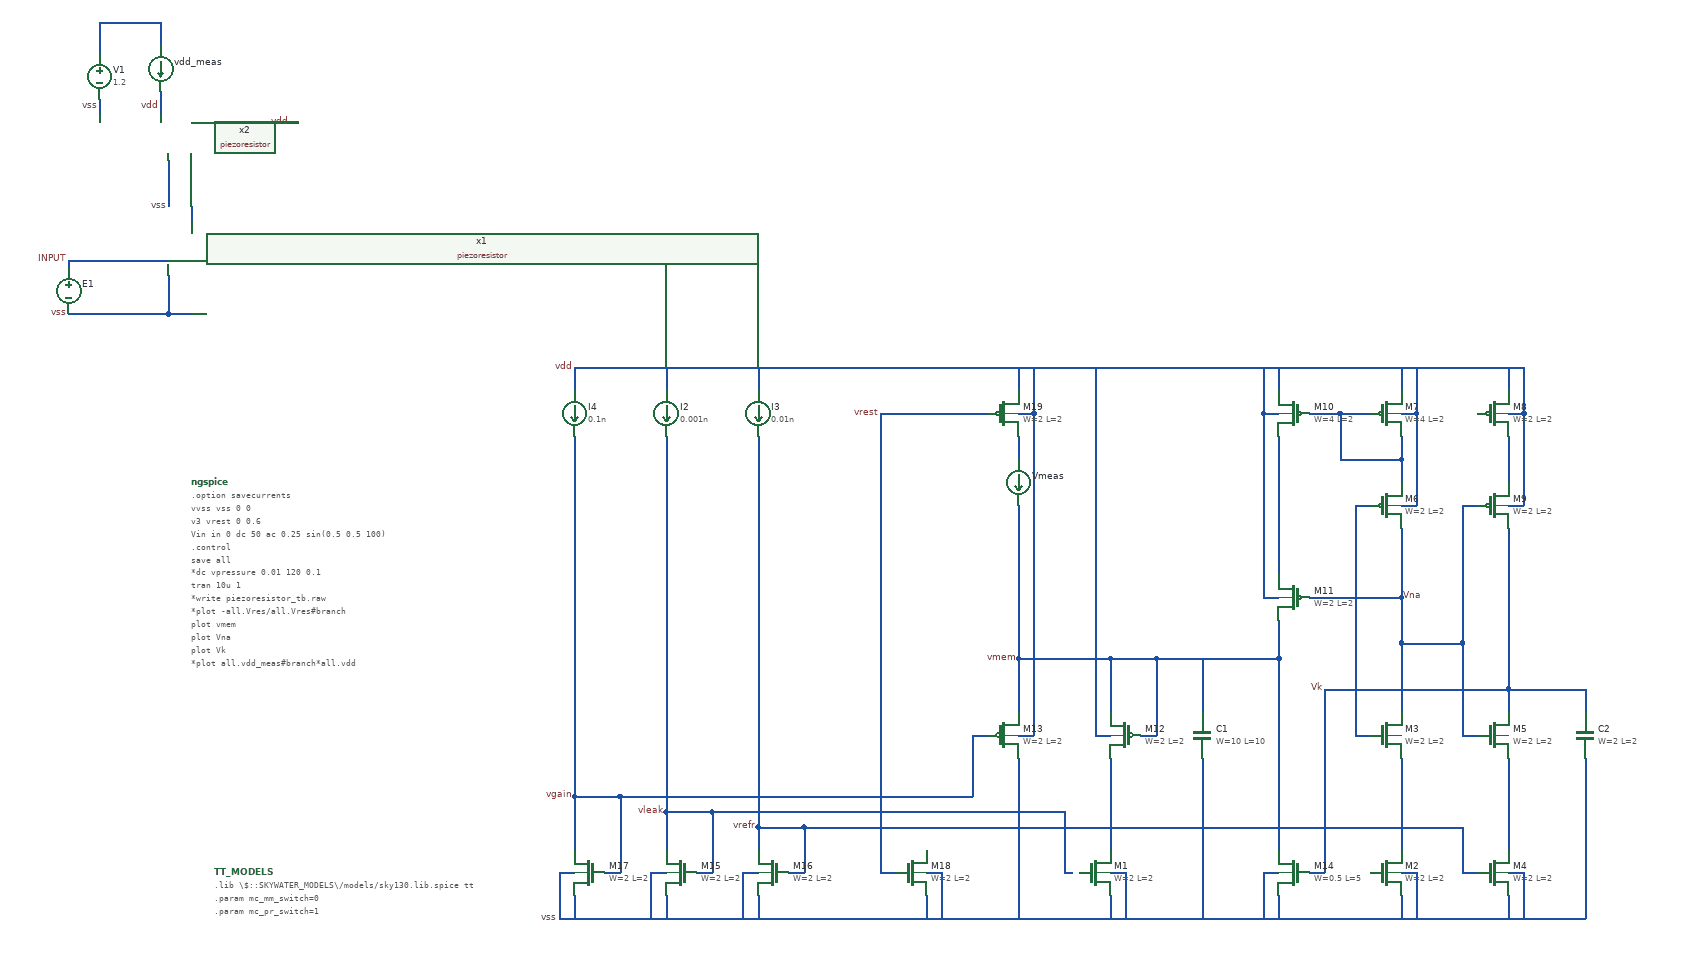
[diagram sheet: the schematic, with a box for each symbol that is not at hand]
v {xschem version=2.9.9 file_version=1.2 

* Copyright 2020 Stefan Frederik Schippers
* 
* Licensed under the Apache License, Version 2.0 (the "License");
* you may not use this file except in compliance with the License.
* You may obtain a copy of the License at
*
*     https://www.apache.org/licenses/LICENSE-2.0
*
* Unless required by applicable law or agreed to in writing, software
* distributed under the License is distributed on an "AS IS" BASIS,
* WITHOUT WARRANTIES OR CONDITIONS OF ANY KIND, either express or implied.
* See the License for the specific language governing permissions and
* limitations under the License.

}
G {}
K {}
V {}
S {}
E {}
N 1100 -1840 1230 -1840 { lab=INPUT}
N 1140 -2150 1140 -2110 { lab=#net1}
N 1140 -2150 1220 -2150 { lab=#net1}
N 1220 -2150 1220 -2120 { lab=#net1}
N 1220 -2060 1220 -2030 { lab=vdd}
N 1140 -2050 1140 -2030 { lab=vss}
N 2840 -1580 2840 -1550 { lab=#net2}
N 1880 -1700 1880 -1670 { lab=vdd}
N 2000 -1700 2000 -1670 { lab=vdd}
N 1760 -1700 1760 -1670 { lab=vdd}
N 2840 -1520 2860 -1520 { lab=vdd}
N 2840 -1640 2860 -1640 { lab=vdd}
N 2980 -1640 3000 -1640 { lab=vdd}
N 2980 -1520 3000 -1520 { lab=vdd}
N 1230 -1770 1260 -1770 { lab=vss}
N 1260 -1910 1260 -1890 { lab=#net3}
N 1100 -1770 1230 -1770 { lab=vss}
N 1230 -1970 1230 -1910 { lab=vss}
N 1100 -1840 1100 -1830 { lab=INPUT}
N 1230 -1820 1230 -1770 { lab=vss}
N 2680 -1700 2680 -1670 { lab=vdd}
N 2840 -1700 2840 -1670 { lab=vdd}
N 2980 -1700 2980 -1670 { lab=vdd}
N 2660 -1640 2680 -1640 { lab=vdd}
N 2760 -1640 2800 -1640 { lab=#net2}
N 2760 -1580 2840 -1580 { lab=#net2}
N 2760 -1640 2760 -1580 { lab=#net2}
N 2660 -1400 2680 -1400 { lab=vdd}
N 2860 -1640 2860 -1520 { lab=vdd}
N 3000 -1640 3000 -1520 { lab=vdd}
N 2840 -1610 2840 -1580 { lab=#net2}
N 2980 -1610 2980 -1550 { lab=#net4}
N 3000 -1700 3000 -1640 { lab=vdd}
N 2860 -1700 2860 -1640 { lab=vdd}
N 2660 -1700 2660 -1640 { lab=vdd}
N 2680 -1610 2680 -1430 { lab=#net5}
N 2660 -1640 2660 -1400 { lab=vdd}
N 2680 -1320 2680 -1070 { lab=vmem}
N 2840 -1340 2840 -1250 { lab=Vna}
N 2980 -1280 2980 -1250 { lab=Vk}
N 2780 -1520 2800 -1520 { lab=#net6}
N 2780 -1520 2780 -1220 { lab=#net6}
N 2780 -1220 2800 -1220 { lab=#net6}
N 2920 -1520 2940 -1520 { lab=Vna}
N 2920 -1340 2920 -1220 { lab=Vna}
N 2920 -1220 2940 -1220 { lab=Vna}
N 2840 -1340 2920 -1340 { lab=Vna}
N 2720 -1400 2840 -1400 { lab=Vna}
N 2740 -1280 2980 -1280 { lab=Vk}
N 2740 -1280 2740 -1040 { lab=Vk}
N 2720 -1040 2740 -1040 { lab=Vk}
N 2840 -1190 2840 -1070 { lab=#net7}
N 2980 -1190 2980 -1070 { lab=#net8}
N 2660 -1040 2680 -1040 { lab=#net9}
N 2660 -1040 2660 -980 { lab=#net9}
N 2840 -1040 2860 -1040 { lab=#net9}
N 2860 -1040 2860 -980 { lab=#net9}
N 2980 -1040 3000 -1040 { lab=#net9}
N 3000 -1040 3000 -980 { lab=#net9}
N 2980 -1010 2980 -980 { lab=#net9}
N 2840 -1010 2840 -980 { lab=#net9}
N 2680 -1010 2680 -980 { lab=#net9}
N 2040 -1040 2060 -1040 { lab=vrefr}
N 2060 -1100 2060 -1040 { lab=vrefr}
N 2920 -1040 2940 -1040 { lab=vrefr}
N 2920 -1100 2920 -1040 { lab=vrefr}
N 2000 -1100 2000 -1070 { lab=vrefr}
N 1260 -2020 1400 -2020 { lab=vdd}
N 2720 -1640 2760 -1640 { lab=#net2}
N 2840 -1400 2840 -1340 { lab=Vna}
N 2920 -1520 2920 -1340 { lab=Vna}
N 2840 -1490 2840 -1400 { lab=Vna}
N 2980 -1490 2980 -1280 { lab=Vk}
N 2000 -1100 2060 -1100 { lab=vrefr}
N 2460 -1040 2480 -1040 { lab=#net9}
N 2480 -1040 2480 -980 { lab=#net9}
N 2460 -1010 2460 -980 { lab=#net9}
N 1980 -1040 2000 -1040 { lab=#net9}
N 1980 -1040 1980 -980 { lab=#net9}
N 2000 -1010 2000 -980 { lab=#net9}
N 1920 -1040 1940 -1040 { lab=vleak}
N 1860 -1040 1880 -1040 { lab=#net9}
N 1860 -1040 1860 -980 { lab=#net9}
N 1880 -1010 1880 -980 { lab=#net9}
N 1880 -1120 1880 -1070 { lab=vleak}
N 2400 -1040 2410 -1040 { lab=vleak}
N 2400 -1120 2400 -1040 { lab=vleak}
N 1940 -1120 2400 -1120 { lab=vleak}
N 1880 -1610 1880 -1120 { lab=vleak}
N 2000 -1610 2000 -1100 { lab=vrefr}
N 1940 -1120 1940 -1040 { lab=vleak}
N 2060 -1100 2920 -1100 { lab=vrefr}
N 1880 -1120 1940 -1120 { lab=vleak}
N 1740 -1040 1760 -1040 { lab=#net9}
N 1740 -1040 1740 -980 { lab=#net9}
N 1760 -1010 1760 -980 { lab=#net9}
N 1760 -1140 1760 -1070 { lab=vgain}
N 1800 -1040 1820 -1040 { lab=vgain}
N 1820 -1140 1820 -1040 { lab=vgain}
N 2460 -1190 2460 -1060 { lab=#net10}
N 2520 -1320 2680 -1320 { lab=vmem}
N 2460 -1320 2460 -1250 { lab=vmem}
N 1760 -1140 1820 -1140 { lab=vgain}
N 2680 -1370 2680 -1320 { lab=vmem}
N 1760 -1610 1760 -1140 { lab=vgain}
N 2500 -1220 2520 -1220 { lab=vmem}
N 2520 -1320 2520 -1220 { lab=vmem}
N 2340 -1190 2340 -980 { lab=#net9}
N 2280 -1220 2300 -1220 { lab=vgain}
N 2280 -1220 2280 -1140 { lab=vgain}
N 1820 -1140 2280 -1140 { lab=vgain}
N 2440 -1220 2460 -1220 { lab=vdd}
N 2440 -1700 2440 -1220 { lab=vdd}
N 2340 -1220 2360 -1220 { lab=vdd}
N 2340 -1320 2460 -1320 { lab=vmem}
N 2340 -1320 2340 -1250 { lab=vmem}
N 2220 -1040 2240 -1040 { lab=#net9}
N 2240 -1040 2240 -980 { lab=#net9}
N 2220 -1010 2220 -980 { lab=#net9}
N 2160 -1640 2160 -1040 { lab=vrest}
N 2160 -1040 2180 -1040 { lab=vrest}
N 2340 -1640 2360 -1640 { lab=vdd}
N 2460 -1320 2520 -1320 { lab=vmem}
N 2340 -1700 2340 -1670 { lab=vdd}
N 2360 -1700 2360 -1640 { lab=vdd}
N 2360 -1640 2360 -1220 { lab=vdd}
N 2160 -1640 2300 -1640 { lab=vrest}
N 2340 -1610 2340 -1580 { lab=#net11}
N 2340 -1520 2340 -1320 { lab=vmem}
N 3080 -1280 3080 -1250 { lab=Vk}
N 2980 -1280 3080 -1280 { lab=Vk}
N 3080 -1190 3080 -980 { lab=#net9}
N 1740 -980 3080 -980 { lab=#net9}
N 1760 -1700 3000 -1700 { lab=vdd}
N 2580 -1190 2580 -980 { lab=#net9}
N 2580 -1320 2580 -1250 { lab=vmem}
C {devices/code_shown.sym} 1260 -1550 0 0 {name=ngspice 
only_toplevel=true 
value=" 
.option savecurrents
vvss vss 0 0
v3 vrest 0 0.6
Vin in 0 dc 50 ac 0.25 sin(0.5 0.5 100)
.control
save all
*dc vpressure 0.01 120 0.1
tran 10u 1
*write piezoresistor_tb.raw
*plot -all.Vres/all.Vres#branch
plot "vmem" 
plot "Vna" 
plot "Vk"
*plot all.vdd_meas#branch*all.vdd
plot all.Vmeas#branch
op
write DPI.raw
wrdata spikes_DPI.csv all.vmem
wrdata pressure_DPI.csv all.Input

.endc
"}
C {devices/lab_pin.sym} 1390 -2020 0 0 {name=l10 sig_type=std_logic lab=vdd}
C {devices/code.sym} 1290 -1040 0 0 {name=TT_MODELS
only_toplevel=true
format="tcleval( @value )"
value=".lib \\\\$::SKYWATER_MODELS\\\\/models/sky130.lib.spice tt

.param mc_mm_switch=0
.param mc_pr_switch=1

"}
C {devices/lab_pin.sym} 1230 -1910 0 0 {name=l3 sig_type=std_logic lab=vss}
C {devices/vsource_arith.sym} 1100 -1800 0 0 {name=E1 VOL=sin(V(IN))}
C {devices/lab_pin.sym} 1100 -1840 0 0 {name=l4 sig_type=std_logic lab=INPUT}
C {devices/ammeter.sym} 2340 -1550 0 1 {name=Vmeas}
C {devices/ammeter.sym} 1220 -2090 0 0 {name=vdd_meas}
C {devices/vsource.sym} 1140 -2080 0 0 {name=V1 value=1.2
}
C {devices/lab_pin.sym} 1140 -2040 0 0 {name=l12 sig_type=std_logic lab=vss}
C {devices/lab_pin.sym} 1220 -2040 0 0 {name=l13 sig_type=std_logic lab=vdd}
C {sky130_fd_pr/nfet_01v8.sym} 2440 -1040 0 0 {name=M1
L=2
W=2
nf=1 
mult=1
ad="'int((nf+1)/2) * W/nf * 0.29'" 
pd="'2*int((nf+1)/2) * (W/nf + 0.29)'"
as="'int((nf+2)/2) * W/nf * 0.29'" 
ps="'2*int((nf+2)/2) * (W/nf + 0.29)'"
nrd="'0.29 / W'" nrs="'0.29 / W'"
sa=0 sb=0 sd=0
model=nfet_01v8
spiceprefix=X
}
C {sky130_fd_pr/nfet_01v8.sym} 2820 -1040 0 0 {name=M2
L=2
W=2
nf=1 
mult=1
ad="'int((nf+1)/2) * W/nf * 0.29'" 
pd="'2*int((nf+1)/2) * (W/nf + 0.29)'"
as="'int((nf+2)/2) * W/nf * 0.29'" 
ps="'2*int((nf+2)/2) * (W/nf + 0.29)'"
nrd="'0.29 / W'" nrs="'0.29 / W'"
sa=0 sb=0 sd=0
model=nfet_01v8
spiceprefix=X
}
C {sky130_fd_pr/nfet_01v8.sym} 2820 -1220 0 0 {name=M3
L=2
W=2
nf=1 
mult=1
ad="'int((nf+1)/2) * W/nf * 0.29'" 
pd="'2*int((nf+1)/2) * (W/nf + 0.29)'"
as="'int((nf+2)/2) * W/nf * 0.29'" 
ps="'2*int((nf+2)/2) * (W/nf + 0.29)'"
nrd="'0.29 / W'" nrs="'0.29 / W'"
sa=0 sb=0 sd=0
model=nfet_01v8
spiceprefix=X
}
C {sky130_fd_pr/cap_mim_m3_1.sym} 2580 -1220 0 0 {name=C1 model=cap_mim_m3_1 W=10 L=10 MF=1 spiceprefix=X}
C {sky130_fd_pr/cap_mim_m3_1.sym} 3080 -1220 0 0 {name=C2 model=cap_mim_m3_1 W=2 L=2 MF=1 spiceprefix=X}
C {sky130_fd_pr/nfet_01v8.sym} 2700 -1040 0 1 {name=M14
L=5
W=0.5
nf=1 
mult=1
ad="'int((nf+1)/2) * W/nf * 0.29'" 
pd="'2*int((nf+1)/2) * (W/nf + 0.29)'"
as="'int((nf+2)/2) * W/nf * 0.29'" 
ps="'2*int((nf+2)/2) * (W/nf + 0.29)'"
nrd="'0.29 / W'" nrs="'0.29 / W'"
sa=0 sb=0 sd=0
model=nfet_01v8
spiceprefix=X
}
C {devices/lab_pin.sym} 2840 -1400 0 1 {name=l2 lab=Vna}
C {devices/lab_pin.sym} 2740 -1280 0 0 {name=l6 lab=Vk}
C {devices/lab_pin.sym} 2340 -1320 0 0 {name=l18 lab=vmem}
C {sky130_fd_pr/nfet_01v8.sym} 2960 -1040 0 0 {name=M4
L=2
W=2
nf=1 
mult=1
ad="'int((nf+1)/2) * W/nf * 0.29'" 
pd="'2*int((nf+1)/2) * (W/nf + 0.29)'"
as="'int((nf+2)/2) * W/nf * 0.29'" 
ps="'2*int((nf+2)/2) * (W/nf + 0.29)'"
nrd="'0.29 / W'" nrs="'0.29 / W'"
sa=0 sb=0 sd=0
model=nfet_01v8
spiceprefix=X
}
C {sky130_fd_pr/nfet_01v8.sym} 2960 -1220 0 0 {name=M5
L=2
W=2
nf=1 
mult=1
ad="'int((nf+1)/2) * W/nf * 0.29'" 
pd="'2*int((nf+1)/2) * (W/nf + 0.29)'"
as="'int((nf+2)/2) * W/nf * 0.29'" 
ps="'2*int((nf+2)/2) * (W/nf + 0.29)'"
nrd="'0.29 / W'" nrs="'0.29 / W'"
sa=0 sb=0 sd=0
model=nfet_01v8
spiceprefix=X
}
C {devices/isource.sym} 1880 -1640 0 1 {name=I2 value=0.001n
}
C {sky130_fd_pr/nfet_01v8.sym} 1900 -1040 0 1 {name=M15
L=2
W=2
nf=1 
mult=1
ad="'int((nf+1)/2) * W/nf * 0.29'" 
pd="'2*int((nf+1)/2) * (W/nf + 0.29)'"
as="'int((nf+2)/2) * W/nf * 0.29'" 
ps="'2*int((nf+2)/2) * (W/nf + 0.29)'"
nrd="'0.29 / W'" nrs="'0.29 / W'"
sa=0 sb=0 sd=0
model=nfet_01v8
spiceprefix=X
}
C {devices/isource.sym} 2000 -1640 0 1 {name=I3 value=0.01n

}
C {sky130_fd_pr/nfet_01v8.sym} 2020 -1040 0 1 {name=M16
L=2
W=2
nf=1 
mult=1
ad="'int((nf+1)/2) * W/nf * 0.29'" 
pd="'2*int((nf+1)/2) * (W/nf + 0.29)'"
as="'int((nf+2)/2) * W/nf * 0.29'" 
ps="'2*int((nf+2)/2) * (W/nf + 0.29)'"
nrd="'0.29 / W'" nrs="'0.29 / W'"
sa=0 sb=0 sd=0
model=nfet_01v8
spiceprefix=X
}
C {devices/isource.sym} 1760 -1640 0 1 {name=I4 value=0.1n
}
C {sky130_fd_pr/nfet_01v8.sym} 1780 -1040 0 1 {name=M17
L=2
W=2
nf=1 
mult=1
ad="'int((nf+1)/2) * W/nf * 0.29'" 
pd="'2*int((nf+1)/2) * (W/nf + 0.29)'"
as="'int((nf+2)/2) * W/nf * 0.29'" 
ps="'2*int((nf+2)/2) * (W/nf + 0.29)'"
nrd="'0.29 / W'" nrs="'0.29 / W'"
sa=0 sb=0 sd=0
model=nfet_01v8
spiceprefix=X
}
C {devices/lab_pin.sym} 1760 -1140 0 0 {name=l23 sig_type=std_logic lab=vgain}
C {devices/lab_pin.sym} 1880 -1120 0 0 {name=l24 sig_type=std_logic lab=vleak}
C {devices/lab_pin.sym} 2000 -1100 0 0 {name=l25 sig_type=std_logic lab=vrefr}
C {devices/lab_pin.sym} 2160 -1640 0 0 {name=l27 sig_type=std_logic lab=vrest}
C {sky130_fd_pr/pfet_01v8.sym} 2820 -1520 0 0 {name=M6
L=2
W=2
nf=1
mult=1
ad="'int((nf+1)/2) * W/nf * 0.29'" 
pd="'2*int((nf+1)/2) * (W/nf + 0.29)'"
as="'int((nf+2)/2) * W/nf * 0.29'" 
ps="'2*int((nf+2)/2) * (W/nf + 0.29)'"
nrd="'0.29 / W'" nrs="'0.29 / W'"
sa=0 sb=0 sd=0
model=pfet_01v8
spiceprefix=X
}
C {sky130_fd_pr/pfet_01v8.sym} 2820 -1640 0 0 {name=M7
L=2
W=4
nf=1
mult=1
ad="'int((nf+1)/2) * W/nf * 0.29'" 
pd="'2*int((nf+1)/2) * (W/nf + 0.29)'"
as="'int((nf+2)/2) * W/nf * 0.29'" 
ps="'2*int((nf+2)/2) * (W/nf + 0.29)'"
nrd="'0.29 / W'" nrs="'0.29 / W'"
sa=0 sb=0 sd=0
model=pfet_01v8
spiceprefix=X
}
C {sky130_fd_pr/pfet_01v8.sym} 2960 -1640 0 0 {name=M8
L=2
W=2
nf=1
mult=1
ad="'int((nf+1)/2) * W/nf * 0.29'" 
pd="'2*int((nf+1)/2) * (W/nf + 0.29)'"
as="'int((nf+2)/2) * W/nf * 0.29'" 
ps="'2*int((nf+2)/2) * (W/nf + 0.29)'"
nrd="'0.29 / W'" nrs="'0.29 / W'"
sa=0 sb=0 sd=0
model=pfet_01v8
spiceprefix=X
}
C {sky130_fd_pr/pfet_01v8.sym} 2960 -1520 0 0 {name=M9
L=2
W=2
nf=1
mult=1
ad="'int((nf+1)/2) * W/nf * 0.29'" 
pd="'2*int((nf+1)/2) * (W/nf + 0.29)'"
as="'int((nf+2)/2) * W/nf * 0.29'" 
ps="'2*int((nf+2)/2) * (W/nf + 0.29)'"
nrd="'0.29 / W'" nrs="'0.29 / W'"
sa=0 sb=0 sd=0
model=pfet_01v8
spiceprefix=X
}
C {sky130_fd_pr/pfet_01v8.sym} 2700 -1640 0 1 {name=M10
L=2
W=4
nf=1
mult=1
ad="'int((nf+1)/2) * W/nf * 0.29'" 
pd="'2*int((nf+1)/2) * (W/nf + 0.29)'"
as="'int((nf+2)/2) * W/nf * 0.29'" 
ps="'2*int((nf+2)/2) * (W/nf + 0.29)'"
nrd="'0.29 / W'" nrs="'0.29 / W'"
sa=0 sb=0 sd=0
model=pfet_01v8
spiceprefix=X
}
C {sky130_fd_pr/pfet_01v8.sym} 2700 -1400 0 1 {name=M11
L=2
W=2
nf=1
mult=1
ad="'int((nf+1)/2) * W/nf * 0.29'" 
pd="'2*int((nf+1)/2) * (W/nf + 0.29)'"
as="'int((nf+2)/2) * W/nf * 0.29'" 
ps="'2*int((nf+2)/2) * (W/nf + 0.29)'"
nrd="'0.29 / W'" nrs="'0.29 / W'"
sa=0 sb=0 sd=0
model=pfet_01v8
spiceprefix=X
}
C {sky130_fd_pr/pfet_01v8.sym} 2480 -1220 0 1 {name=M12
L=2
W=2
nf=1
mult=1
ad="'int((nf+1)/2) * W/nf * 0.29'" 
pd="'2*int((nf+1)/2) * (W/nf + 0.29)'"
as="'int((nf+2)/2) * W/nf * 0.29'" 
ps="'2*int((nf+2)/2) * (W/nf + 0.29)'"
nrd="'0.29 / W'" nrs="'0.29 / W'"
sa=0 sb=0 sd=0
model=pfet_01v8
spiceprefix=X
}
C {sky130_fd_pr/pfet_01v8.sym} 2320 -1220 0 0 {name=M13
L=2
W=2
nf=1
mult=1
ad="'int((nf+1)/2) * W/nf * 0.29'" 
pd="'2*int((nf+1)/2) * (W/nf + 0.29)'"
as="'int((nf+2)/2) * W/nf * 0.29'" 
ps="'2*int((nf+2)/2) * (W/nf + 0.29)'"
nrd="'0.29 / W'" nrs="'0.29 / W'"
sa=0 sb=0 sd=0
model=pfet_01v8
spiceprefix=X
}
C {piezoresistor.sym} 1350 -1960 0 0 {name=x2}
C {sky130_fd_pr/nfet_01v8.sym} 2200 -1040 0 0 {name=M18
L=2
W=2
nf=1 
mult=1
ad="'int((nf+1)/2) * W/nf * 0.29'" 
pd="'2*int((nf+1)/2) * (W/nf + 0.29)'"
as="'int((nf+2)/2) * W/nf * 0.29'" 
ps="'2*int((nf+2)/2) * (W/nf + 0.29)'"
nrd="'0.29 / W'" nrs="'0.29 / W'"
sa=0 sb=0 sd=0
model=nfet_01v8
spiceprefix=X
}
C {piezoresistor.sym} 1350 -1830 0 0 {name=x1}
C {sky130_fd_pr/pfet_01v8.sym} 2320 -1640 0 0 {name=M19
L=2
W=2
nf=1
mult=1
ad="'int((nf+1)/2) * W/nf * 0.29'" 
pd="'2*int((nf+1)/2) * (W/nf + 0.29)'"
as="'int((nf+2)/2) * W/nf * 0.29'" 
ps="'2*int((nf+2)/2) * (W/nf + 0.29)'"
nrd="'0.29 / W'" nrs="'0.29 / W'"
sa=0 sb=0 sd=0
model=pfet_01v8
spiceprefix=X
}
C {devices/lab_pin.sym} 1100 -1770 0 0 {name=l36 sig_type=std_logic lab=vss}
C {devices/lab_pin.sym} 1760 -1700 0 0 {name=l1 sig_type=std_logic lab=vdd}
C {devices/lab_pin.sym} 1740 -980 0 0 {name=l5 sig_type=std_logic lab=vss}
